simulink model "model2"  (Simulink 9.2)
settings: Solver=ode4  StartTime=0.0  StopTime=10  FixedStep=0.001  RelTol=1e-3  AbsTol=1e-6
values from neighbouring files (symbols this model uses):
  Beq = 5.4    [experiment_file.m]    (also in setup_ip01_2_configuration.m)
  Bp = 2.40e-3    (= 0.0024)    [experiment_file.m]    (also in setup_sp_configuration.m)
  Eff_g = 1    [setup_ip01_2_configuration.m]
  Eff_m = 1    [setup_ip01_2_configuration.m]
  g = 9.81    [experiment_file.m]    (also in setup_sp_configuration.m)
  IC_ALPHA0 = IC_ALPHA0 / 180 * pi    (= 0)    [setup.m]    (also in setup_lab_ip01_2_sip.m)
  IMAX_UPM = 3    [setup_ip01_2_configuration.m]
  Ip = 1.1987e-3    (= 0.0011987)    [experiment_file.m]    (also in setup_sp_configuration.m = Mp * Lp^2 / 12)
  K = [ 0 0 0 0 ]    [setup_lab_ip01_2_sip.m]
  Kg = 3.71    [setup_ip01_2_configuration.m]
  Km = 0.804e-3 * K_RDPS2RPM    [setup_ip01_2_configuration.m]
  Kt = 1.088 * K_OZ2N * K_IN2M    [setup_ip01_2_configuration.m]
  lp = 1.7780e-1    (= 0.1778)    [experiment_file.m]    (also in setup_sp_configuration.m = 7 * K_IN2M)
  Mc = 1.0731    [experiment_file.m]    (also in setup.m = Mc + Eff_g * Kg^2 * Jm / r_mp^2; setup_lab_ip01_2_sip.m = Mc + Eff_g * Kg^2 * Jm / r_mp^2)
  Mp = 1.27e-1    (= 0.127)    [experiment_file.m]    (also in setup_sp_configuration.m)
  r_mp = 0.5 / 2 * K_IN2M    [setup_ip01_2_configuration.m]
  Rm = 2.6    [setup_ip01_2_configuration.m]
  VMAX_UPM = 13    [setup_ip01_2_configuration.m]
libraries: simulink_extras x1

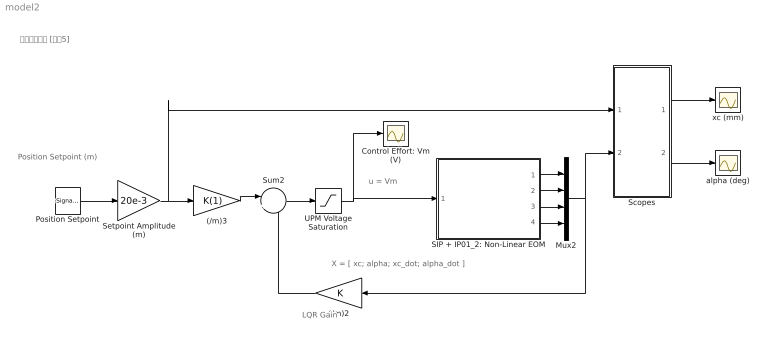
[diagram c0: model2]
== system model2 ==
  note: 計測制御工学 [問題5]
  note: u = Vm
  note: X = [ xc; alpha; xc_dot; alpha_dot ]
  note: LQR Gain
  note: Position Setpoint (m)
  (/m)2 : Gain  Gain=K  Multiplication=Matrix(K*u)
  (/m)3 : Gain  Gain=K(1)
  Control Effort: Vm (V) : Scope
  Mux2 : Mux
  Position Setpoint : SignalGenerator  WaveForm=square  Frequency=0.2
  SIP + IP01_2: Non-Linear EOM : Subsystem
  Scopes : Subsystem
  Setpoint Amplitude (m) : Gain  Gain=20e-3
  Sum2 : Sum  Inputs=|+-
  UPM Voltage Saturation : Saturate  UpperLimit=VMAX_UPM  LowerLimit=- VMAX_UPM
  alpha (deg) : Scope
  xc (mm) : Scope
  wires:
  UPM Voltage Saturation/1 -> SIP + IP01_2: Non-Linear EOM/1(Vm (V)), Control Effort: Vm (V)/1
  Sum2/1 -> UPM Voltage Saturation/1
  Mux2/1 -> Scopes/2(X_eom), (/m)2/1
  Position Setpoint/1 -> Setpoint Amplitude (m)/1
  Setpoint Amplitude (m)/1 -> (/m)3/1, Scopes/1(xc_des)
  (/m)2/1 -> Sum2/2
  (/m)3/1 -> Sum2/1
  SIP + IP01_2: Non-Linear EOM/1(xc (m)) -> Mux2/1
  SIP + IP01_2: Non-Linear EOM/2(alpha (rd)) -> Mux2/2
  SIP + IP01_2: Non-Linear EOM/3(xc_dot (m/s)) -> Mux2/3
  SIP + IP01_2: Non-Linear EOM/4(alpha_dot (rd/s)) -> Mux2/4
  Scopes/1(Out1) -> xc (mm)/1
  Scopes/2(Out2) -> alpha (deg)/1

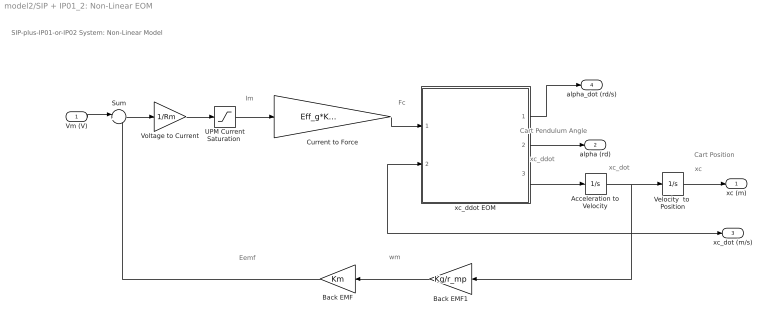
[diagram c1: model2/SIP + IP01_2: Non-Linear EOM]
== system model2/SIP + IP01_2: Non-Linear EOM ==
  note: SIP-plus-IP01-or-IP02 System: Non-Linear Model
  note: Fc
  note: Im
  note: Eemf
  note: wm
  note: xc_dot
  note: xc_ddot
  note: xc
  note: Cart Position
  note: Cart Pendulum Angle
  Vm (V) : Inport
  Acceleration to Velocity : Integrator
  Back EMF : Gain  Gain=Km
  Back EMF1 : Gain  Gain=Kg/r_mp
  Current to Force : Gain  Gain=Eff_g*Kg*Eff_m*Kt/r_mp
  Sum : Sum  Inputs=|+-
  "UPM Current Saturation " : Saturate  UpperLimit=IMAX_UPM  LowerLimit=- IMAX_UPM
  Velocity  to  Position : Integrator
  Voltage to Current : Gain  Gain=1/Rm
  xc_ddot EOM : Subsystem
  xc (m) : Outport
  alpha (rd) : Outport  Port=2
  xc_dot (m/s) : Outport  Port=3  InitialOutput=0
  alpha_dot (rd/s) : Outport  Port=4  InitialOutput=0
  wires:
  Sum/1 -> Voltage to Current/1
  Voltage to Current/1 -> "UPM Current Saturation "/1
  Acceleration to Velocity/1 -> xc_dot (m/s)/1, xc_ddot EOM/2(xc_dot (m/s)), Back EMF1/1, Velocity  to  Position/1
  Back EMF1/1 -> Back EMF/1
  Vm (V)/1 -> Sum/1
  Velocity  to  Position/1 -> xc (m)/1
  Back EMF/1 -> Sum/2
  "UPM Current Saturation "/1 -> Current to Force/1
  Current to Force/1 -> xc_ddot EOM/1(Fc (N))
  xc_ddot EOM/3(xc_ddot (m/s^2)) -> Acceleration to Velocity/1
  xc_ddot EOM/1(alpha_dot (rd/s)) -> alpha_dot (rd/s)/1
  xc_ddot EOM/2(alpha (rd)) -> alpha (rd)/1

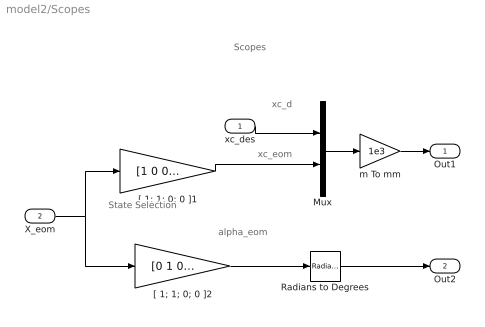
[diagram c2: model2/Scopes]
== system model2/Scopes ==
  note: xc_eom
  note: State Selection
  note: alpha_eom
  note: xc_d
  note: Scopes
  xc_des : Inport
  X_eom : Inport  Port=2
  Mux : Mux  Inputs=2
  Radians to Degrees : simulink_extras/Transformations/Radians to Degrees
  "[ 1; 1; 0; 0 ]1" : Gain  Gain=[1 0 0 0]  Multiplication=Matrix(K*u)
  "[ 1; 1; 0; 0 ]2" : Gain  Gain=[0 1 0 0]  Multiplication=Matrix(K*u)
  m To mm : Gain  Gain=1e3
  Out1 : Outport
  Out2 : Outport  Port=2
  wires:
  Mux/1 -> m To mm/1
  m To mm/1 -> Out1/1
  "[ 1; 1; 0; 0 ]1"/1 -> Mux/2
  xc_des/1 -> Mux/1
  X_eom/1 -> "[ 1; 1; 0; 0 ]1"/1, "[ 1; 1; 0; 0 ]2"/1
  Radians to Degrees/1 -> Out2/1
  "[ 1; 1; 0; 0 ]2"/1 -> Radians to Degrees/1

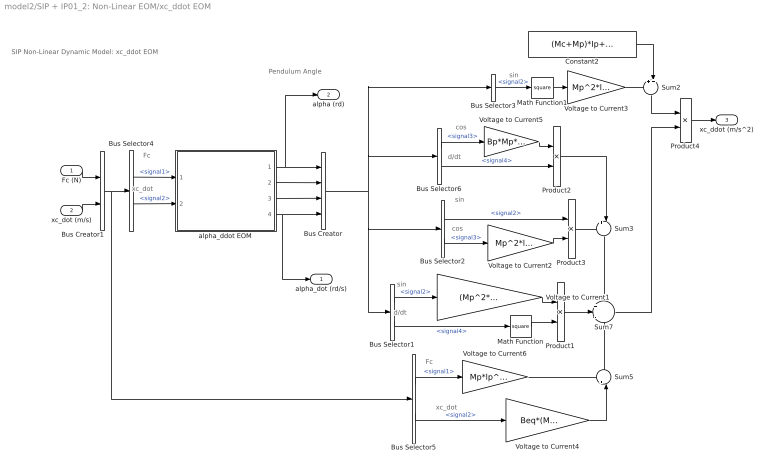
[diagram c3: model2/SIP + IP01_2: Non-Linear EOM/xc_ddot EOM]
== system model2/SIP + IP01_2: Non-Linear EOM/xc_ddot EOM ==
  note: xc_dot
  note: Fc
  note: xc_dot
  note: Fc
  note: d/dt
  note: cos
  note: Pendulum Angle
  note: sin
  note: cos
  note: sin
  note: sin
  note: d/dt
  note: SIP Non-Linear Dynamic Model: xc_ddot EOM
  Fc (N) : Inport
  xc_dot (m/s) : Inport  Port=2
  Bus Creator : BusCreator  Inputs=4
  Bus Creator1 : BusCreator  Inputs=2
  Bus Selector1 : BusSelector  OutputSignals=signal2,signal4
  Bus Selector2 : BusSelector  OutputSignals=signal2,signal3
  Bus Selector3 : BusSelector  OutputSignals=signal2
  Bus Selector4 : BusSelector  OutputSignals=signal1,signal2
  Bus Selector5 : BusSelector  OutputSignals=signal1,signal2
  Bus Selector6 : BusSelector  OutputSignals=signal3,signal4
  Constant2 : Constant  Value=(Mc+Mp)*Ip+Mc*Mp*lp^2
  Math Function : Math  Operator=square
  Math Function1 : Math  Operator=square
  Product1 : Product
  Product2 : Product
  Product3 : Product
  Product4 : Product  Inputs=/*
  Sum2 : Sum  Inputs=++|
  Sum3 : Sum  Inputs=+-|
  Sum5 : Sum  Inputs=+-|
  Sum7 : Sum  Inputs=+|-|+
  Voltage to Current1 : Gain  Gain=(Mp^2*lp^3+Ip*Mp*lp)
  Voltage to Current2 : Gain  Gain=Mp^2*lp^2*g
  Voltage to Current3 : Gain  Gain=Mp^2*lp^2
  Voltage to Current4 : Gain  Gain=Beq*(Mp*lp^2+Ip)
  Voltage to Current5 : Gain  Gain=Bp*Mp*lp
  Voltage to Current6 : Gain  Gain=Mp*lp^2+Ip
  alpha_ddot EOM : Subsystem
  alpha_dot (rd/s) : Outport
  alpha (rd) : Outport  Port=2
  xc_ddot (m/s^2) : Outport  Port=3
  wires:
  Voltage to Current4/1 -> Sum5/2
  Voltage to Current6/1 -> Sum5/1
  Sum5/1 -> Sum7/3
  Sum3/1 -> Sum7/1
  Product3/1 -> Sum3/1
  Product2/1 -> Sum3/2
  Sum7/1 -> Product4/2
  Bus Selector5/2 -> Voltage to Current4/1  "<signal2>"
  Bus Selector5/1 -> Voltage to Current6/1  "<signal1>"
  Voltage to Current5/1 -> Product2/1
  Bus Selector2/2 -> Voltage to Current2/1  "<signal3>"
  Bus Selector2/1 -> Product3/1  "<signal2>"
  Bus Selector6/2 -> Product2/2  "<signal4>"
  Bus Selector6/1 -> Voltage to Current5/1  "<signal3>"
  Bus Selector1/1 -> Voltage to Current1/1  "<signal2>"
  Bus Selector1/2 -> Math Function/1  "<signal4>"
  Bus Selector4/2 -> alpha_ddot EOM/2(xc_dot (m/s))  "<signal2>"
  Bus Selector4/1 -> alpha_ddot EOM/1(Fc (N))  "<signal1>"
  Bus Creator1/1 -> Bus Selector5/1, Bus Selector4/1
  xc_dot (m/s)/1 -> Bus Creator1/2
  Fc (N)/1 -> Bus Creator1/1
  alpha_ddot EOM/4(d(a)/dt) -> Bus Creator/4, alpha_dot (rd/s)/1
  alpha_ddot EOM/3(cos(a)) -> Bus Creator/3
  alpha_ddot EOM/2(sin(a)) -> Bus Creator/2
  alpha_ddot EOM/1(alpha) -> alpha (rd)/1, Bus Creator/1
  Product4/1 -> xc_ddot (m/s^2)/1
  Product1/1 -> Sum7/2
  Constant2/1 -> Sum2/2
  Voltage to Current3/1 -> Sum2/1
  Math Function1/1 -> Voltage to Current3/1
  Bus Selector3/1 -> Math Function1/1  "<signal2>"
  Voltage to Current2/1 -> Product3/2
  Math Function/1 -> Product1/2
  Voltage to Current1/1 -> Product1/1
  Bus Creator/1 -> Bus Selector6/1, Bus Selector3/1, Bus Selector1/1, Bus Selector2/1
  Sum2/1 -> Product4/1

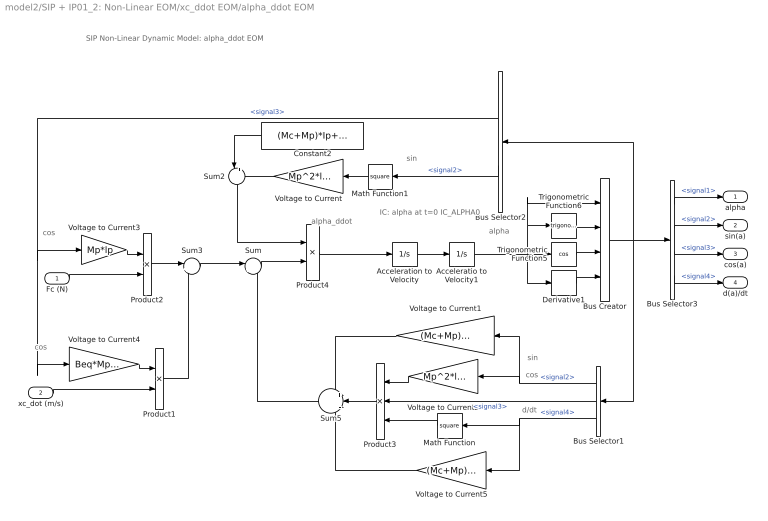
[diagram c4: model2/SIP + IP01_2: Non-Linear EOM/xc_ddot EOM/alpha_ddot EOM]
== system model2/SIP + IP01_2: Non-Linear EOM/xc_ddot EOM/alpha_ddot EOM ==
  note: cos
  note: alpha_ddot
  note: IC: alpha at t=0 IC_ALPHA0
  note: SIP Non-Linear Dynamic Model: alpha_ddot EOM
  note: alpha
  note: sin
  note: cos
  note: sin
  note: cos
  note: d/dt
  Fc (N) : Inport
  xc_dot (m/s) : Inport  Port=2
  Acceleratio to Velocity1 : Integrator  InitialCondition=IC_ALPHA0
  Acceleration to Velocity : Integrator
  Bus Creator : BusCreator  Inputs=4
  Bus Selector1 : BusSelector  OutputSignals=signal2,signal3,signal4
  Bus Selector2 : BusSelector  OutputSignals=signal3,signal2
  Bus Selector3 : BusSelector  OutputSignals=signal1,signal2,signal3,signal4
  Constant2 : Constant  Value=(Mc+Mp)*Ip+Mc*Mp*lp^2
  Derivative1 : Derivative
  Math Function : Math  Operator=square
  Math Function1 : Math  Operator=square
  Product1 : Product
  Product2 : Product
  Product3 : Product  Inputs=3
  Product4 : Product  Inputs=/*
  Sum : Sum  Inputs=|++
  Sum2 : Sum  Inputs=|++
  Sum3 : Sum  Inputs=|+-
  Sum5 : Sum  Inputs=+|-|-
  Trigonometric Function5 : Trigonometry  Operator=cos
  Trigonometric Function6 : Trigonometry
  Voltage to Current : Gain  Gain=Mp^2*lp^2
  Voltage to Current1 : Gain  Gain=(Mc+Mp)*Mp*lp*g
  Voltage to Current2 : Gain  Gain=Mp^2*lp^2
  Voltage to Current3 : Gain  Gain=Mp*lp
  Voltage to Current4 : Gain  Gain=Beq*Mp*lp
  Voltage to Current5 : Gain  Gain=(Mc+Mp)*Bp
  alpha : Outport  InitialOutput=0
  sin(a) : Outport  Port=2  InitialOutput=0
  cos(a) : Outport  Port=3  InitialOutput=0
  d(a)/dt : Outport  Port=4  InitialOutput=0
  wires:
  Sum5/1 -> Sum/2
  Voltage to Current5/1 -> Sum5/3
  Voltage to Current1/1 -> Sum5/1
  Product3/1 -> Sum5/2
  Sum3/1 -> Sum/1
  Product1/1 -> Sum3/2
  Product2/1 -> Sum3/1
  Voltage to Current4/1 -> Product1/1
  xc_dot (m/s)/1 -> Product1/2
  Fc (N)/1 -> Product2/2
  Voltage to Current3/1 -> Product2/1
  Acceleratio to Velocity1/1 -> Bus Creator/1, Trigonometric Function6/1, Derivative1/1, Trigonometric Function5/1
  Bus Selector3/4 -> d(a)/dt/1  "<signal4>"
  Bus Selector3/3 -> cos(a)/1  "<signal3>"
  Bus Selector3/2 -> sin(a)/1  "<signal2>"
  Bus Selector3/1 -> alpha/1  "<signal1>"
  Bus Selector1/3 -> Voltage to Current5/1, Math Function/1  "<signal4>"
  Bus Selector1/2 -> Product3/2  "<signal3>"
  Voltage to Current2/1 -> Product3/1
  Bus Selector2/1 -> Voltage to Current4/1, Voltage to Current3/1  "<signal3>"
  Bus Creator/1 -> Bus Selector3/1, Bus Selector1/1, Bus Selector2/1
  Derivative1/1 -> Bus Creator/4
  Trigonometric Function5/1 -> Bus Creator/3
  Trigonometric Function6/1 -> Bus Creator/2
  Constant2/1 -> Sum2/1
  Math Function1/1 -> Voltage to Current/1
  Bus Selector2/2 -> Math Function1/1  "<signal2>"
  Voltage to Current/1 -> Sum2/2
  Sum/1 -> Product4/2
  Sum2/1 -> Product4/1
  Math Function/1 -> Product3/3
  Product4/1 -> Acceleration to Velocity/1
  Bus Selector1/1 -> Voltage to Current2/1, Voltage to Current1/1  "<signal2>"
  Acceleration to Velocity/1 -> Acceleratio to Velocity1/1
